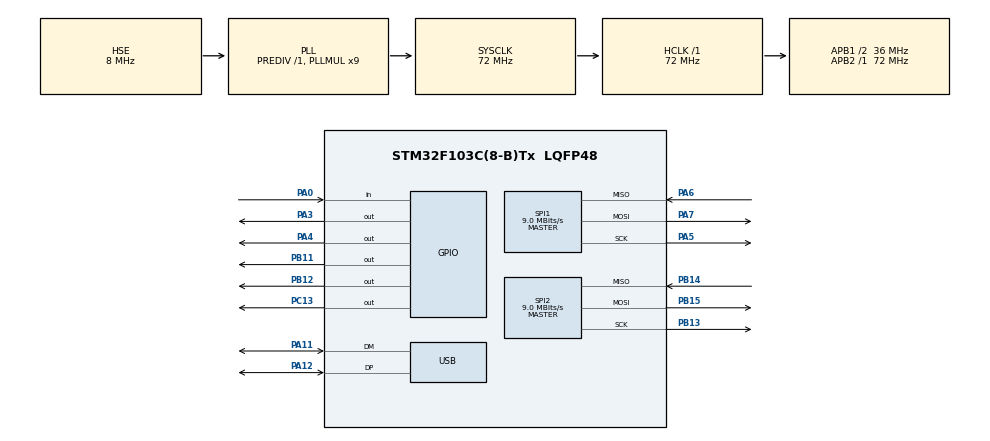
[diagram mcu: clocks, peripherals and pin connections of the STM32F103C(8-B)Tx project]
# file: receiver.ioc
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Mcu.Family=STM32F1
Mcu.Name=STM32F103C(8-B)Tx
Mcu.Package=LQFP48
NVIC.PriorityGroup=NVIC_PRIORITYGROUP_4
NVIC.USB_LP_CAN1_RX0_IRQn=true\:0\:0\:false\:false\:true\:false\:true\:true
PA0-WKUP.GPIO_PuPd=GPIO_PULLUP
PA0-WKUP.Signal=GPIO_Input
PA11.Mode=Device
PA11.Signal=USB_DM
PA12.Mode=Device
PA12.Signal=USB_DP
PA13.Mode=Serial_Wire
PA13.Signal=SYS_JTMS-SWDIO
PA14.Mode=Serial_Wire
PA14.Signal=SYS_JTCK-SWCLK
PA3.Signal=GPIO_Output
PA4.Signal=GPIO_Output
PA5.Mode=Full_Duplex_Master
PA5.Signal=SPI1_SCK
PA6.Mode=Full_Duplex_Master
PA6.Signal=SPI1_MISO
PA7.Mode=Full_Duplex_Master
PA7.Signal=SPI1_MOSI
PB11.Signal=GPIO_Output
PB12.Signal=GPIO_Output
PB13.Mode=Full_Duplex_Master
PB13.Signal=SPI2_SCK
PB14.Mode=Full_Duplex_Master
PB14.Signal=SPI2_MISO
PB15.Mode=Full_Duplex_Master
PB15.Signal=SPI2_MOSI
PC13-TAMPER-RTC.GPIO_ModeDefaultOutputPP=GPIO_MODE_OUTPUT_PP
PC13-TAMPER-RTC.GPIO_PuPd=GPIO_NOPULL
PC13-TAMPER-RTC.Signal=GPIO_Output
PD0-OSC_IN.Mode=HSE-External-Oscillator
PD0-OSC_IN.Signal=RCC_OSC_IN
PD1-OSC_OUT.Mode=HSE-External-Oscillator
PD1-OSC_OUT.Signal=RCC_OSC_OUT
ProjectManager.HeapSize=0x200
ProjectManager.StackSize=0x400
ProjectManager.TargetToolchain=STM32CubeIDE
RCC.AHBFreq_Value=72000000
RCC.APB1CLKDivider=RCC_HCLK_DIV2
RCC.APB1Freq_Value=36000000
RCC.APB1TimFreq_Value=72000000
RCC.APB2Freq_Value=72000000
RCC.APB2TimFreq_Value=72000000
RCC.HCLKFreq_Value=72000000
RCC.PLLMUL=RCC_PLL_MUL9
RCC.SYSCLKFreq_VALUE=72000000
RCC.SYSCLKSource=RCC_SYSCLKSOURCE_PLLCLK
RCC.USBFreq_Value=48000000
RCC.USBPrescaler=RCC_USBCLKSOURCE_PLL_DIV1_5
SPI1.BaudRatePrescaler=SPI_BAUDRATEPRESCALER_8
SPI1.CalculateBaudRate=9.0 MBits/s
SPI1.Direction=SPI_DIRECTION_2LINES
SPI1.Mode=SPI_MODE_MASTER
SPI1.VirtualType=VM_MASTER
SPI2.BaudRatePrescaler=SPI_BAUDRATEPRESCALER_4
SPI2.CalculateBaudRate=9.0 MBits/s
SPI2.Direction=SPI_DIRECTION_2LINES
SPI2.Mode=SPI_MODE_MASTER
SPI2.VirtualType=VM_MASTER
USB_DEVICE.CLASS_NAME_FS=CDC
USB_DEVICE.VirtualMode=Cdc
USB_DEVICE.VirtualModeFS=Cdc_FS
VP_USB_DEVICE_VS_USB_DEVICE_CDC_FS.Mode=CDC_FS
board=custom

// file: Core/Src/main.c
/* USER CODE BEGIN Header */
/**
  ******************************************************************************
  * @file           : main.c
  * @brief          : Main program body
  ******************************************************************************
  * @attention
  *
  * Copyright (c) 2025 STMicroelectronics.
  * All rights reserved.
  *
  * This software is licensed under terms that can be found in the LICENSE file
  * in the root directory of this software component.
  * If no LICENSE file comes with this software, it is provided AS-IS.
  *
  ******************************************************************************
  */
/* USER CODE END Header */
#include "main.h"
#include "usb_device.h"

/* USER CODE BEGIN Includes */
#include "usbd_cdc_if.h"
#include "string.h"
#include <stdio.h>
#include <stdint.h>
#include <stdbool.h>

#include "nrf24l01.h"
/* USER CODE END Includes */

/* USER CODE BEGIN PD */

#define PAYLOAD_LENGTH       2

// GPIO Pins
#define NRFA_CE_GPIO_PORT 	GPIOB
#define NRFA_CE_GPIO_PIN    GPIO_PIN_0
#define NRFA_CS_GPIO_PORT 	GPIOA
#define NRFA_CS_GPIO_PIN    GPIO_PIN_4
#define NRFA_IRQ_GPIO_PORT 	GPIOA
#define NRFA_IRQ_GPIO_PIN 	GPIO_PIN_3

#define NRFB_CE_GPIO_PORT 	GPIOB
#define NRFB_CE_GPIO_PIN    GPIO_PIN_11
#define NRFB_CS_GPIO_PORT 	GPIOB
#define NRFB_CS_GPIO_PIN    GPIO_PIN_12
#define NRFB_IRQ_GPIO_PORT 	GPIOB
#define NRFB_IRQ_GPIO_PIN 	GPIO_PIN_10

#define NRF_FIFO_RX_EMPTY_BIT  (1U << 0)

/* USB framing */
#define USB_FRAME_LEN        4       // 0xFE, 0xED, payload[0], payload[1]
#define USB_QUEUE_CAPACITY   64      // number of frames buffered

/* USER CODE END PD */

SPI_HandleTypeDef hspi1;
SPI_HandleTypeDef hspi2;

/* USER CODE BEGIN PV */
extern USBD_HandleTypeDef hUsbDeviceFS;

NRF24L01_HandleTypeDef nrf_rx_A;
NRF24L01_HandleTypeDef nrf_rx_B;

volatile uint8_t nrfA_pending = 0;
volatile uint8_t nrfB_pending = 0;

/* RX buffers from radios */
uint8_t rx_pipe_A = 0;
uint8_t rx_pipe_B = 0;

uint8_t rx_buffer_A[PAYLOAD_LENGTH] = {0, };
uint8_t rx_buffer_B[PAYLOAD_LENGTH] = {0, };

/* ---- USB packet queue (ring buffer of framed packets) ---- */

typedef struct {
	uint8_t data[USB_FRAME_LEN];
} UsbFrame;

typedef struct {
	uint16_t head;  // next write
	uint16_t tail;  // next read
	UsbFrame buf[USB_QUEUE_CAPACITY];
} UsbQueue;

static UsbQueue g_usb_queue = {0};

static inline int usbq_is_empty(const UsbQueue *q) {
	return (q->head == q->tail);
}

static inline int usbq_is_full(const UsbQueue *q) {
	return ((q->head + 1U) % USB_QUEUE_CAPACITY) == q->tail;
}

/* push a frame; returns 1 on success, 0 if full */
static int usbq_push(UsbQueue *q, const uint8_t *data, uint8_t len) {
	if (len > USB_FRAME_LEN) {
		return 0;
	}
	if (usbq_is_full(q)) {
		/* queue overflow -> drop frame */
		return 0;
	}

	uint16_t head = q->head;
	for (uint8_t i = 0; i < len; i++) {
		q->buf[head].data[i] = data[i];
	}
	q->head = (uint16_t)((head + 1U) % USB_QUEUE_CAPACITY);
	return 1;
}

/* pop a frame; returns 1 on success, 0 if empty */
static int usbq_pop(UsbQueue *q, UsbFrame *out) {
	if (usbq_is_empty(q)) {
		return 0;
	}
	uint16_t tail = q->tail;
	*out = q->buf[tail];  // struct copy, only 4 bytes
	q->tail = (uint16_t)((tail + 1U) % USB_QUEUE_CAPACITY);
	return 1;
}

/* USER CODE END PV */

void SystemClock_Config(void);
static void MX_GPIO_Init(void);
static void MX_SPI1_Init(void);
static void MX_SPI2_Init(void);

/* USER CODE BEGIN 0 */

static void usb_wait_configured(void) {
	while (hUsbDeviceFS.dev_state != USBD_STATE_CONFIGURED) {
		// Rapid LED Flashing - USB connecting state
		HAL_GPIO_TogglePin(GPIOC, GPIO_PIN_13);
		HAL_Delay(100);
	}
}

/* This still blocks until the packet is handed to the USB stack.
 * Now we call it from the main loop using queued frames instead of
 * directly from the radio handlers.
 */
static void send_bytes(const uint8_t *buf, uint16_t len) {
	while (CDC_Transmit_FS((uint8_t *) buf, len) == USBD_BUSY);
}

void HAL_GPIO_EXTI_Callback(uint16_t GPIO_Pin)
{
	if (GPIO_Pin == nrf_rx_A.IRQ_GPIO_PIN) {
		nrfA_pending = 1;
	} else if (GPIO_Pin == nrf_rx_B.IRQ_GPIO_PIN) {
		nrfB_pending = 1;
	}
}

void NRF_Configure_Handles(void) {
	nrf_rx_A.hspi          = &hspi1;
	nrf_rx_A.CS_GPIO_PORT  = NRFA_CS_GPIO_PORT;
	nrf_rx_A.CS_GPIO_PIN   = NRFA_CS_GPIO_PIN;
	nrf_rx_A.CE_GPIO_PORT  = NRFA_CE_GPIO_PORT;
	nrf_rx_A.CE_GPIO_PIN   = NRFA_CE_GPIO_PIN;
	nrf_rx_A.IRQ_GPIO_PORT = NRFA_IRQ_GPIO_PORT;
	nrf_rx_A.IRQ_GPIO_PIN  = NRFA_IRQ_GPIO_PIN;

	nrf_rx_B.hspi          = &hspi2;
	nrf_rx_B.CS_GPIO_PORT  = NRFB_CS_GPIO_PORT;
	nrf_rx_B.CS_GPIO_PIN   = NRFB_CS_GPIO_PIN;
	nrf_rx_B.CE_GPIO_PORT  = NRFB_CE_GPIO_PORT;
	nrf_rx_B.CE_GPIO_PIN   = NRFB_CE_GPIO_PIN;
	nrf_rx_B.IRQ_GPIO_PORT = NRFB_IRQ_GPIO_PORT;
	nrf_rx_B.IRQ_GPIO_PIN  = NRFB_IRQ_GPIO_PIN;
}

/* USER CODE END 0 */

int main(void)
{

  /* MCU Configuration--------------------------------------------------------*/

  /* Reset of all peripherals, Initializes the Flash interface and the Systick. */
  HAL_Init();

  /* Configure the system clock */
  SystemClock_Config();

  /* Initialize all configured peripherals */
  MX_GPIO_Init();
  MX_USB_DEVICE_Init();
  MX_SPI1_Init();
  MX_SPI2_Init();
  /* USER CODE BEGIN 2 */

  usb_wait_configured();
  // Turn LED off
  HAL_GPIO_WritePin(GPIOC, GPIO_PIN_13, GPIO_PIN_SET);

  NRF_Configure_Handles();

  NRF24L01_SetRxPayloadWidths(&nrf_rx_A, PAYLOAD_LENGTH, 2000);
  NRF24L01_SetRxPayloadWidths(&nrf_rx_B, PAYLOAD_LENGTH, 2000);

  // Radios
  uint8_t RxAddress0_A[5] = {0xB3, 0xB4, 0xB5, 0xB6, 0x00};
  uint8_t RxAddress1_A[5] = {0xB3, 0xB4, 0xB5, 0xB6, 0x01};
  uint8_t RxAddress2_A = 0x02;
  uint8_t RxAddress3_A = 0x03;

  uint8_t RxAddress0_B[5] = {0xB3, 0xB4, 0xB5, 0xB6, 0x04};
  uint8_t RxAddress1_B[5] = {0xB3, 0xB4, 0xB5, 0xB6, 0x05};
  uint8_t RxAddress2_B = 0x06;
  uint8_t RxAddress3_B = 0x07;

  NRF24L01_RxInit(&nrf_rx_A, 70, NRF24L01_DATA_RATE_2MBPS, 2000);
  NRF24L01_RxInit(&nrf_rx_B, 85, NRF24L01_DATA_RATE_2MBPS, 2000);

  NRF24L01_SetRxAddress(&nrf_rx_A, NRF24L01_RX_ADDRESS_P0, RxAddress0_A, 2000);
  NRF24L01_SetRxAddress(&nrf_rx_A, NRF24L01_RX_ADDRESS_P1, RxAddress1_A, 2000);
  NRF24L01_SetRxAddress(&nrf_rx_A, NRF24L01_RX_ADDRESS_P2, &RxAddress2_A, 2000);
  NRF24L01_SetRxAddress(&nrf_rx_A, NRF24L01_RX_ADDRESS_P3, &RxAddress3_A, 2000);

  NRF24L01_SetRxAddress(&nrf_rx_B, NRF24L01_RX_ADDRESS_P0, RxAddress0_B, 2000);
  NRF24L01_SetRxAddress(&nrf_rx_B, NRF24L01_RX_ADDRESS_P1, RxAddress1_B, 2000);
  NRF24L01_SetRxAddress(&nrf_rx_B, NRF24L01_RX_ADDRESS_P2, &RxAddress2_B, 2000);
  NRF24L01_SetRxAddress(&nrf_rx_B, NRF24L01_RX_ADDRESS_P3, &RxAddress3_B, 2000);

  /* USER CODE END 2 */

  /* Infinite loop */
  while (1) {

    /* USER CODE BEGIN 3 */

    /* ---- Handle radio A IRQ ---- */
    if (nrfA_pending) {
    	nrfA_pending = 0;

    	/* Drain RX FIFO and enqueue framed USB packets */
    	while ((NRF24L01_GetFIFOStatus(&nrf_rx_A, 200) & NRF_FIFO_RX_EMPTY_BIT) == 0) {
    		NRF24L01_RxReceive(&nrf_rx_A, rx_buffer_A, &rx_pipe_A, 200);

    		uint8_t frame[USB_FRAME_LEN];
    		frame[0] = 0xFE;                 // sync byte 1
    		frame[1] = 0xED;                 // sync byte 2
    		frame[2] = rx_buffer_A[0];       // payload byte 0 (e.g. device_id)
    		frame[3] = rx_buffer_A[1];       // payload byte 1 (e.g. mask)

    		(void)usbq_push(&g_usb_queue, frame, USB_FRAME_LEN);
    	}
    	/* If your nRF driver does NOT clear RX_DR in RxReceive,
    	 * you should explicitly clear it here by writing STATUS.
    	 */
    	// uint8_t status = NRF24L01_GetStatus(&nrf_rx_A, 200);
    	// if (status & NRF24L01_RX_DR_MASK) {
    	// 	NRF24L01_WriteRegister(&nrf_rx_A,
    	// 	                        NRF24L01_REG_STATUS,
    	// 	                        NRF24L01_RX_DR_MASK,
    	// 	                        200);
    	// }
    }

    /* ---- Handle radio B IRQ ---- */
    if (nrfB_pending) {
    	nrfB_pending = 0;

    	while ((NRF24L01_GetFIFOStatus(&nrf_rx_B, 200) & NRF_FIFO_RX_EMPTY_BIT) == 0) {
    		NRF24L01_RxReceive(&nrf_rx_B, rx_buffer_B, &rx_pipe_B, 200);

    		uint8_t frame[USB_FRAME_LEN];
    		frame[0] = 0xFE;
    		frame[1] = 0xED;
    		frame[2] = rx_buffer_B[0];
    		frame[3] = rx_buffer_B[1];

    		(void)usbq_push(&g_usb_queue, frame, USB_FRAME_LEN);
    	}
    	// Same RX_DR comment as above if needed.
    }

    /* ---- Flush USB queue ---- */
    while (!usbq_is_empty(&g_usb_queue)) {
    	UsbFrame out;
    	if (!usbq_pop(&g_usb_queue, &out)) {
    		break;
    	}
    	/* This blocks until the USB stack accepts the packet */
    	send_bytes(out.data, USB_FRAME_LEN);
    }

  }

  /* USER CODE END 3 */
}

void SystemClock_Config(void)
{
  RCC_OscInitTypeDef RCC_OscInitStruct = {0};
  RCC_ClkInitTypeDef RCC_ClkInitStruct = {0};
  RCC_PeriphCLKInitTypeDef PeriphClkInit = {0};

  /** Initializes the RCC Oscillators according to the specified parameters
  * in the RCC_OscInitTypeDef structure.
  */
  RCC_OscInitStruct.OscillatorType = RCC_OSCILLATORTYPE_HSE;
  RCC_OscInitStruct.HSEState = RCC_HSE_ON;
  RCC_OscInitStruct.HSEPredivValue = RCC_HSE_PREDIV_DIV1;
  RCC_OscInitStruct.HSIState = RCC_HSI_ON;
  RCC_OscInitStruct.PLL.PLLState = RCC_PLL_ON;
  RCC_OscInitStruct.PLL.PLLSource = RCC_PLLSOURCE_HSE;
  RCC_OscInitStruct.PLL.PLLMUL = RCC_PLL_MUL9;
  if (HAL_RCC_OscConfig(&RCC_OscInitStruct) != HAL_OK)
  {
    Error_Handler();
  }

  /** Initializes the CPU, AHB and APB buses clocks
  */
  RCC_ClkInitStruct.ClockType = RCC_CLOCKTYPE_HCLK|RCC_CLOCKTYPE_SYSCLK
                              |RCC_CLOCKTYPE_PCLK1|RCC_CLOCKTYPE_PCLK2;
  RCC_ClkInitStruct.SYSCLKSource = RCC_SYSCLKSOURCE_PLLCLK;
  RCC_ClkInitStruct.AHBCLKDivider = RCC_SYSCLK_DIV1;
  RCC_ClkInitStruct.APB1CLKDivider = RCC_HCLK_DIV2;
  RCC_ClkInitStruct.APB2CLKDivider = RCC_HCLK_DIV1;

  if (HAL_RCC_ClockConfig(&RCC_ClkInitStruct, FLASH_LATENCY_2) != HAL_OK)
  {
    Error_Handler();
  }
  PeriphClkInit.PeriphClockSelection = RCC_PERIPHCLK_USB;
  PeriphClkInit.UsbClockSelection = RCC_USBCLKSOURCE_PLL_DIV1_5;
  if (HAL_RCCEx_PeriphCLKConfig(&PeriphClkInit) != HAL_OK)
  {
    Error_Handler();
  }
}

static void MX_SPI1_Init(void)
{

  /* SPI1 parameter configuration*/
  hspi1.Instance = SPI1;
  hspi1.Init.Mode = SPI_MODE_MASTER;
  hspi1.Init.Direction = SPI_DIRECTION_2LINES;
  hspi1.Init.DataSize = SPI_DATASIZE_8BIT;
  hspi1.Init.CLKPolarity = SPI_POLARITY_LOW;
  hspi1.Init.CLKPhase = SPI_PHASE_1EDGE;
  hspi1.Init.NSS = SPI_NSS_SOFT;
  hspi1.Init.BaudRatePrescaler = SPI_BAUDRATEPRESCALER_8;
  hspi1.Init.FirstBit = SPI_FIRSTBIT_MSB;
  hspi1.Init.TIMode = SPI_TIMODE_DISABLE;
  hspi1.Init.CRCCalculation = SPI_CRCCALCULATION_DISABLE;
  hspi1.Init.CRCPolynomial = 10;
  if (HAL_SPI_Init(&hspi1) != HAL_OK)
  {
    Error_Handler();
  }

}

static void MX_SPI2_Init(void)
{

  /* SPI2 parameter configuration*/
  hspi2.Instance = SPI2;
  hspi2.Init.Mode = SPI_MODE_MASTER;
  hspi2.Init.Direction = SPI_DIRECTION_2LINES;
  hspi2.Init.DataSize = SPI_DATASIZE_8BIT;
  hspi2.Init.CLKPolarity = SPI_POLARITY_LOW;
  hspi2.Init.CLKPhase = SPI_PHASE_1EDGE;
  hspi2.Init.NSS = SPI_NSS_SOFT;
  hspi2.Init.BaudRatePrescaler = SPI_BAUDRATEPRESCALER_4;
  hspi2.Init.FirstBit = SPI_FIRSTBIT_MSB;
  hspi2.Init.TIMode = SPI_TIMODE_DISABLE;
  hspi2.Init.CRCCalculation = SPI_CRCCALCULATION_DISABLE;
  hspi2.Init.CRCPolynomial = 10;
  if (HAL_SPI_Init(&hspi2) != HAL_OK)
  {
    Error_Handler();
  }

}

static void MX_GPIO_Init(void)
{
  GPIO_InitTypeDef GPIO_InitStruct = {0};

  /* GPIO Ports Clock Enable */
  __HAL_RCC_GPIOC_CLK_ENABLE();
  __HAL_RCC_GPIOD_CLK_ENABLE();
  __HAL_RCC_GPIOA_CLK_ENABLE();
  __HAL_RCC_GPIOB_CLK_ENABLE();

  /*Configure GPIO pin Output Level */
  HAL_GPIO_WritePin(GPIOC, GPIO_PIN_13, GPIO_PIN_RESET);

  /*Configure GPIO pin Output Level */
  HAL_GPIO_WritePin(GPIOA, GPIO_PIN_4, GPIO_PIN_RESET);

  /*Configure GPIO pin Output Level */
  HAL_GPIO_WritePin(GPIOB, GPIO_PIN_0|GPIO_PIN_11|GPIO_PIN_12, GPIO_PIN_RESET);

  /*Configure GPIO pin : PC13 */
  GPIO_InitStruct.Pin = GPIO_PIN_13;
  GPIO_InitStruct.Mode = GPIO_MODE_OUTPUT_PP;
  GPIO_InitStruct.Pull = GPIO_NOPULL;
  GPIO_InitStruct.Speed = GPIO_SPEED_FREQ_LOW;
  HAL_GPIO_Init(GPIOC, &GPIO_InitStruct);

  /*Configure GPIO pin : PA3 */
  GPIO_InitStruct.Pin = GPIO_PIN_3;
  GPIO_InitStruct.Mode = GPIO_MODE_IT_FALLING;
  GPIO_InitStruct.Pull = GPIO_NOPULL;
  HAL_GPIO_Init(GPIOA, &GPIO_InitStruct);

  /*Configure GPIO pin : PA4 */
  GPIO_InitStruct.Pin = GPIO_PIN_4;
  GPIO_InitStruct.Mode = GPIO_MODE_OUTPUT_PP;
  GPIO_InitStruct.Pull = GPIO_NOPULL;
  GPIO_InitStruct.Speed = GPIO_SPEED_FREQ_LOW;
  HAL_GPIO_Init(GPIOA, &GPIO_InitStruct);

  /*Configure GPIO pins : PB0 PB11 PB12 */
  GPIO_InitStruct.Pin = GPIO_PIN_0|GPIO_PIN_11|GPIO_PIN_12;
  GPIO_InitStruct.Mode = GPIO_MODE_OUTPUT_PP;
  GPIO_InitStruct.Pull = GPIO_NOPULL;
  GPIO_InitStruct.Speed = GPIO_SPEED_FREQ_LOW;
  HAL_GPIO_Init(GPIOB, &GPIO_InitStruct);

  /*Configure GPIO pin : PB10 */
  GPIO_InitStruct.Pin = GPIO_PIN_10;
  GPIO_InitStruct.Mode = GPIO_MODE_IT_FALLING;
  GPIO_InitStruct.Pull = GPIO_NOPULL;
  HAL_GPIO_Init(GPIOB, &GPIO_InitStruct);

  /* EXTI interrupt init*/
  HAL_NVIC_SetPriority(EXTI3_IRQn, 0, 0);
  HAL_NVIC_EnableIRQ(EXTI3_IRQn);

  HAL_NVIC_SetPriority(EXTI15_10_IRQn, 0, 0);
  HAL_NVIC_EnableIRQ(EXTI15_10_IRQn);

}

void Error_Handler(void)
{
  __disable_irq();
  while (1)
  {
  }
}
